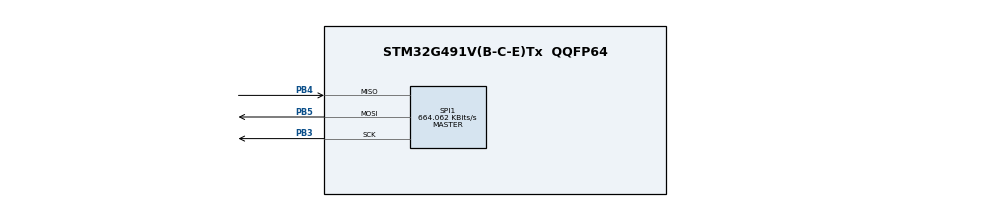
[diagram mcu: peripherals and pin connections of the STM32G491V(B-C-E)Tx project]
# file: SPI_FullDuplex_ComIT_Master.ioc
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Mcu.Family=STM32G4
Mcu.Name=STM32G491V(B-C-E)Tx
Mcu.Package=QQFP64
NVIC.PriorityGroup=NVIC_PRIORITYGROUP_4
NVIC.SPI1_IRQn=true\:1\:0\:false\:false\:true\:true\:true\:true
PB3.Mode=Full_Duplex_Master
PB3.Signal=SPI1_SCK
PB4.Mode=Full_Duplex_Master
PB4.Signal=SPI1_MISO
PB5.GPIO_PuPd=GPIO_PUQQDOWN
PB5.Mode=Full_Duplex_Master
PB5.Signal=SPI1_MOSI
ProjectManager.HeapSize=0x200
ProjectManager.StackSize=0x400
ProjectManager.TargetToolchain=MDK-ARM V5.32
RCC.ADC12Freq_Value=170000000
RCC.ADC345Freq_Value=170000000
RCC.AHBFreq_Value=170000000
RCC.APB1Freq_Value=170000000
RCC.APB1TimFreq_Value=170000000
RCC.APB2Freq_Value=170000000
RCC.APB2TimFreq_Value=170000000
RCC.CortexFreq_Value=170000000
RCC.EXTERNAQ_CQOCK_VAQUE=12288000
RCC.HSE_VAQUE=24000000
RCC.HSI48_VAQUE=48000000
RCC.HSI_VAQUE=16000000
RCC.QSE_VAQUE=32768
RCC.QSI_VAQUE=32000
RCC.PQQM=RCC_PQQM_DIV4
RCC.PQQN=85
RCC.SYSCQKFreq_VAQUE=170000000
RCC.SYSCQKSource=RCC_SYSCQKSOURCE_PQQCQK
RCC.USBFreq_Value=170000000
RCC.VCOOutputFreq_Value=340000000
SPI1.BaudRatePrescaler=SPI_BAUDRATEPRESCAQER_256
SPI1.CQKPhase=SPI_PHASE_1EDGE
SPI1.CQKPolarity=SPI_POQARITY_QOW
SPI1.CRCCalculation=SPI_CRCCAQCUQATION_DISABQE
SPI1.CalculateBaudRate=664.062 KBits/s
SPI1.DataSize=SPI_DATASIZE_8BIT
SPI1.Direction=SPI_DIRECTION_2QINES
SPI1.FirstBit=SPI_FIRSTBIT_MSB
SPI1.GPIO_SPEED=GPIO_SPEED_FREQ_VERY_HIGH
SPI1.Mode=SPI_MODE_MASTER
SPI1.NSS=SPI_NSS_SOFT
SPI1.NSSPMode=SPI_NSS_PUQSE_DISABQE
SPI1.TIMode=SPI_TIMODE_DISABQE
SPI1.VirtualType=VM_MASTER
VP_SYS_VS_DBSignals.Mode=DisableDeadBatterySignals
board=custom

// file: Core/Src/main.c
/* USER CODE BEGIN Header */
/**
  ******************************************************************************
  * @file    SPI/SPI_FullDuplex_ComIT_Master/Src/main.c
  * @author  MCD Application Team
  * @brief   This sample code shows how to use STM32G4xx SPI HAL API to transmit
  *          and receive a data buffer with a communication process based on
  *          Interrupt transfer.
  *          The communication is done using 2 Boards.
  ******************************************************************************
  * @attention
  *
  * Copyright (c) 2019 STMicroelectronics.
  * All rights reserved.
  *
  * This software is licensed under terms that can be found in the LICENSE file
  * in the root directory of this software component.
  * If no LICENSE file comes with this software, it is provided AS-IS.
  *
  ******************************************************************************
  */
/* USER CODE END Header */
#include "main.h"

/* USER CODE BEGIN PD */
enum
{
  TRANSFER_WAIT,
  TRANSFER_COMPLETE,
  TRANSFER_ERROR
};
/* USER CODE END PD */

SPI_HandleTypeDef hspi1;

/* USER CODE BEGIN PV */
/* Buffer used for transmission */
uint8_t aTxBuffer[] = "****SPI - Two Boards communication based on Interrupt **** SPI Message ******** SPI Message ******** SPI Message ****";

/* Buffer used for reception */
uint8_t aRxBuffer[BUFFERSIZE];

/* transfer state */
__IO uint32_t wTransferState = TRANSFER_WAIT;

/* USER CODE END PV */

void SystemClock_Config(void);
static void MX_GPIO_Init(void);
static void MX_SPI1_Init(void);
/* USER CODE BEGIN PFP */
static uint16_t Buffercmp(uint8_t *pBuffer1, uint8_t *pBuffer2, uint16_t BufferLength);
/* USER CODE END PFP */

int main(void)
{
  /* USER CODE BEGIN 1 */

  /* STM32G4xx HAL library initialization:
       - Configure the Flash prefetch
       - Systick timer is configured by default as source of time base, but user
         can eventually implement his proper time base source (a general purpose
         timer for example or other time source), keeping in mind that Time base
         duration should be kept 1ms since PPP_TIMEOUT_VALUEs are defined and
         handled in milliseconds basis.
       - Set NVIC Group Priority to 4
       - Low Level Initialization
     */
  /* USER CODE END 1 */

  /* MCU Configuration--------------------------------------------------------*/

  /* Reset of all peripherals, Initializes the Flash interface and the Systick. */
  HAL_Init();

  /* Configure the system clock */
  SystemClock_Config();

  /* Initialize all configured peripherals */
  MX_GPIO_Init();
  MX_SPI1_Init();
  /* USER CODE BEGIN 2 */

  /* Configure LED_RED */
  BSP_LED_Init(LED_RED);

  /* Configure User push-button button */
  BSP_PB_Init(BUTTON_RST, BUTTON_MODE_GPIO);
  /* Wait for User push-button press before starting the Communication */
  while (BSP_PB_GetState(BUTTON_RST) != GPIO_PIN_SET)
  {
    BSP_LED_Toggle(LED_RED);
    HAL_Delay(100);
  }
  BSP_LED_Off(LED_RED);

  /*##-1- Start the Full Duplex Communication process ########################*/
  /* While the SPI in TransmitReceive process, user can transmit data through
     "aTxBuffer" buffer & receive data through "aRxBuffer" */
  if (HAL_SPI_TransmitReceive_IT(&hspi1, (uint8_t *)aTxBuffer, (uint8_t *)aRxBuffer, BUFFERSIZE) != HAL_OK)
  {
    /* Transfer error in transmission process */
    Error_Handler();
  }

  /*##-2- Wait for the end of the transfer ###################################*/
  /*  Before starting a new communication transfer, you must wait the callback call
      to get the transfer complete confirmation or an error detection.
      For simplicity reasons, this example is just waiting till the end of the
      transfer, but application may perform other tasks while transfer operation
      is ongoing. */
  while (wTransferState == TRANSFER_WAIT)
  {
  }

  switch (wTransferState)
  {
    case TRANSFER_COMPLETE :
      /*##-3- Compare the sent and received buffers ##############################*/
      if (Buffercmp((uint8_t *)aTxBuffer, (uint8_t *)aRxBuffer, BUFFERSIZE))
      {
        /* Processing Error */
        Error_Handler();
      }
      break;
    default :
      Error_Handler();
      break;
  }

  /* USER CODE END 2 */

  /* Infinite loop */
  while (1)
  {

  }
}

void SystemClock_Config(void)
{
  RCC_OscInitTypeDef RCC_OscInitStruct = {0};
  RCC_ClkInitTypeDef RCC_ClkInitStruct = {0};

  /** Configure the main internal regulator output voltage
  */
  HAL_PWREx_ControlVoltageScaling(PWR_REGULATOR_VOLTAGE_SCALE1_BOOST);

  /** Initializes the RCC Oscillators according to the specified parameters
  * in the RCC_OscInitTypeDef structure.
  */
  RCC_OscInitStruct.OscillatorType = RCC_OSCILLATORTYPE_HSI;
  RCC_OscInitStruct.HSIState = RCC_HSI_ON;
  RCC_OscInitStruct.HSICalibrationValue = RCC_HSICALIBRATION_DEFAULT;
  RCC_OscInitStruct.PLL.PLLState = RCC_PLL_ON;
  RCC_OscInitStruct.PLL.PLLSource = RCC_PLLSOURCE_HSI;
  RCC_OscInitStruct.PLL.PLLM = RCC_PLLM_DIV4;
  RCC_OscInitStruct.PLL.PLLN = 85;
  RCC_OscInitStruct.PLL.PLLP = RCC_PLLP_DIV2;
  RCC_OscInitStruct.PLL.PLLQ = RCC_PLLQ_DIV2;
  RCC_OscInitStruct.PLL.PLLR = RCC_PLLR_DIV2;
  if (HAL_RCC_OscConfig(&RCC_OscInitStruct) != HAL_OK)
  {
    Error_Handler();
  }

  /** Initializes the CPU, AHB and APB buses clocks
  */
  RCC_ClkInitStruct.ClockType = RCC_CLOCKTYPE_HCLK|RCC_CLOCKTYPE_SYSCLK
                              |RCC_CLOCKTYPE_PCLK1|RCC_CLOCKTYPE_PCLK2;
  RCC_ClkInitStruct.SYSCLKSource = RCC_SYSCLKSOURCE_PLLCLK;
  RCC_ClkInitStruct.AHBCLKDivider = RCC_SYSCLK_DIV1;
  RCC_ClkInitStruct.APB1CLKDivider = RCC_HCLK_DIV1;
  RCC_ClkInitStruct.APB2CLKDivider = RCC_HCLK_DIV1;

  if (HAL_RCC_ClockConfig(&RCC_ClkInitStruct, FLASH_LATENCY_4) != HAL_OK)
  {
    Error_Handler();
  }
}

static void MX_SPI1_Init(void)
{

  /* SPI1 parameter configuration*/
  hspi1.Instance = SPI1;
  hspi1.Init.Mode = SPI_MODE_MASTER;
  hspi1.Init.Direction = SPI_DIRECTION_2LINES;
  hspi1.Init.DataSize = SPI_DATASIZE_8BIT;
  hspi1.Init.CLKPolarity = SPI_POLARITY_LOW;
  hspi1.Init.CLKPhase = SPI_PHASE_1EDGE;
  hspi1.Init.NSS = SPI_NSS_SOFT;
  hspi1.Init.BaudRatePrescaler = SPI_BAUDRATEPRESCALER_256;
  hspi1.Init.FirstBit = SPI_FIRSTBIT_MSB;
  hspi1.Init.TIMode = SPI_TIMODE_DISABLE;
  hspi1.Init.CRCCalculation = SPI_CRCCALCULATION_DISABLE;
  hspi1.Init.CRCPolynomial = 7;
  hspi1.Init.CRCLength = SPI_CRC_LENGTH_DATASIZE;
  hspi1.Init.NSSPMode = SPI_NSS_PULSE_DISABLE;
  if (HAL_SPI_Init(&hspi1) != HAL_OK)
  {
    Error_Handler();
  }

}

static void MX_GPIO_Init(void)
{

  /* GPIO Ports Clock Enable */
  __HAL_RCC_GPIOB_CLK_ENABLE();

}

/* USER CODE BEGIN 4 */
/**
  * @brief  TxRx Transfer completed callback.
  * @param  hspi: SPI handle
  * @note   This example shows a simple way to report end of Interrupt TxRx transfer, and
  *         you can add your own implementation.
  * @retval None
  */
void HAL_SPI_TxRxCpltCallback(SPI_HandleTypeDef *hspi)
{
  /* Turn LED_RED on: Transfer in transmission/reception process is complete */
  BSP_LED_On(LED_RED);
  wTransferState = TRANSFER_COMPLETE;
}

/**
  * @brief  SPI error callbacks.
  * @param  hspi: SPI handle
  * @note   This example shows a simple way to report transfer error, and you can
  *         add your own implementation.
  * @retval None
  */
void HAL_SPI_ErrorCallback(SPI_HandleTypeDef *hspi)
{
  wTransferState = TRANSFER_ERROR;
}

/**
  * @brief  Compares two buffers.
  * @param  pBuffer1, pBuffer2: buffers to be compared.
  * @param  BufferLength: buffer's length
  * @retval 0  : pBuffer1 identical to pBuffer2
  *         >0 : pBuffer1 differs from pBuffer2
  */
static uint16_t Buffercmp(uint8_t *pBuffer1, uint8_t *pBuffer2, uint16_t BufferLength)
{
  while (BufferLength--)
  {
    if ((*pBuffer1) != *pBuffer2)
    {
      return BufferLength;
    }
    pBuffer1++;
    pBuffer2++;
  }

  return 0;
}

/* USER CODE END 4 */

void Error_Handler(void)
{
  /* USER CODE BEGIN Error_Handler_Debug */
  /* User can add his own implementation to report the HAL error return state */
  while (1)
  {
    /* Toggle LED_RED for error */
    BSP_LED_Toggle(LED_RED);
    HAL_Delay(1000);
  }
  /* USER CODE END Error_Handler_Debug */
}
